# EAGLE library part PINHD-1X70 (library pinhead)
PIN HEADER 70 pol. Grid 2.54mm

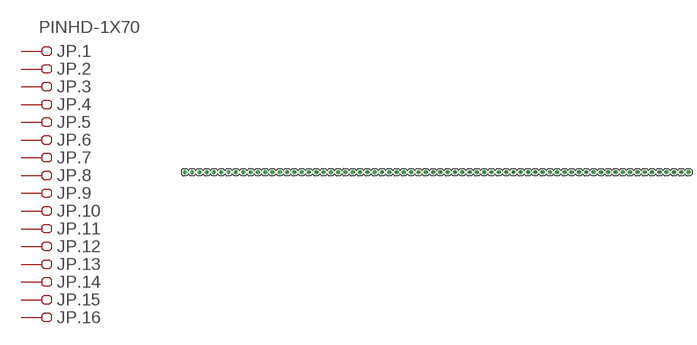
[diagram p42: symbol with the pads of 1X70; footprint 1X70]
Designator prefix JP; gates .1=PINHD_1V .2=PINHD_1 .3=PINHD_1 .4=PINHD_1 .5=PINHD_1 .6=PINHD_1 .7=PINHD_1 .8=PINHD_1 .9=PINHD_1 .10=PINHD_1 .11=PINHD_1 .12=PINHD_1 .13=PINHD_1 .14=PINHD_1 .15=PINHD_1 .16=PINHD_1 .17=PINHD_1 .18=PINHD_1 .19=PINHD_1 .20=PINHD_1 .21=PINHD_1 .22=PINHD_1 .23=PINHD_1 .24=PINHD_1 .25=PINHD_1 .26=PINHD_1 .27=PINHD_1 .28=PINHD_1 .29=PINHD_1 .30=PINHD_1 .31=PINHD_1 .32=PINHD_1 .33=PINHD_1 .34=PINHD_1 .35=PINHD_1 .36=PINHD_1 .37=PINHD_1 .38=PINHD_1 .39=PINHD_1 .40=PINHD_1 .41=PINHD_1 .42=PINHD_1 .43=PINHD_1 .44=PINHD_1 .45=PINHD_1 .46=PINHD_1 .47=PINHD_1 .48=PINHD_1 .49=PINHD_1 .50=PINHD_1 .51=PINHD_1 .52=PINHD_1 .53=PINHD_1 .54=PINHD_1 .55=PINHD_1 .56=PINHD_1 .57=PINHD_1 .58=PINHD_1 .59=PINHD_1 .60=PINHD_1 .61=PINHD_1 .62=PINHD_1 .63=PINHD_1 .64=PINHD_1 .65=PINHD_1 .66=PINHD_1 .67=PINHD_1 .68=PINHD_1 .69=PINHD_1 .70=PINHD_1

## PINHD-1X70  [1X70]
1  .1:1  pas
2  .2:1  pas
3  .3:1  pas
4  .4:1  pas
5  .5:1  pas
6  .6:1  pas
7  .7:1  pas
8  .8:1  pas
9  .9:1  pas
10  .10:1  pas
11  .11:1  pas
12  .12:1  pas
13  .13:1  pas
14  .14:1  pas
15  .15:1  pas
16  .16:1  pas
17  .17:1  pas
18  .18:1  pas
19  .19:1  pas
20  .20:1  pas
21  .21:1  pas
22  .22:1  pas
23  .23:1  pas
24  .24:1  pas
25  .25:1  pas
26  .26:1  pas
27  .27:1  pas
28  .28:1  pas
29  .29:1  pas
30  .30:1  pas
31  .31:1  pas
32  .32:1  pas
33  .33:1  pas
34  .34:1  pas
35  .35:1  pas
36  .36:1  pas
37  .37:1  pas
38  .38:1  pas
39  .39:1  pas
40  .40:1  pas
41  .41:1  pas
42  .42:1  pas
43  .43:1  pas
44  .44:1  pas
45  .45:1  pas
46  .46:1  pas
47  .47:1  pas
48  .48:1  pas
49  .49:1  pas
50  .50:1  pas
51  .51:1  pas
52  .52:1  pas
53  .53:1  pas
54  .54:1  pas
55  .55:1  pas
56  .56:1  pas
57  .57:1  pas
58  .58:1  pas
59  .59:1  pas
60  .60:1  pas
61  .61:1  pas
62  .62:1  pas
63  .63:1  pas
64  .64:1  pas
65  .65:1  pas
66  .66:1  pas
67  .67:1  pas
68  .68:1  pas
69  .69:1  pas
70  .70:1  pas

## Footprint 1X70 (pad centres in mm)
PIN HEADER 70 pol. Grid 2.54mm
drill 1.016: 1 -87.63,0; 2 -85.09,0; 3 -82.55,0; 4 -80.01,0; 5 -77.47,0; 6 -74.93,0; 7 -72.39,0; 8 -69.85,0; 9 -67.31,0; 10 -64.77,0; 11 -62.23,0; 12 -59.69,0; 13 -57.15,0; 14 -54.61,0; 15 -52.07,0; 16 -49.53,0; 17 -46.99,0; 18 -44.45,0; 19 -41.91,0; 20 -39.37,0; 21 -36.83,0; 22 -34.29,0; 23 -31.75,0; 24 -29.21,0; 25 -26.67,0; 26 -24.13,0; 27 -21.59,0; 28 -19.05,0; 29 -16.51,0; 30 -13.97,0; 31 -11.43,0; 32 -8.89,0; 33 -6.35,0; 34 -3.81,0; 35 -1.27,0; 36 1.27,0; 37 3.81,0; 38 6.35,0; 39 8.89,0; 40 11.43,0; 41 13.97,0; 42 16.51,0; 43 19.05,0; 44 21.59,0; 45 24.13,0; 46 26.67,0; 47 29.21,0; 48 31.75,0; 49 34.29,0; 50 36.83,0; 51 39.37,0; 52 41.91,0; 53 44.45,0; 54 46.99,0; 55 49.53,0; 56 52.07,0; 57 54.61,0; 58 57.15,0; 59 59.69,0; 60 62.23,0; 61 64.77,0; 62 67.31,0; 63 69.85,0; 64 72.39,0; 65 74.93,0; 66 77.47,0; 67 80.01,0; 68 82.55,0; 69 85.09,0; 70 87.63,0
